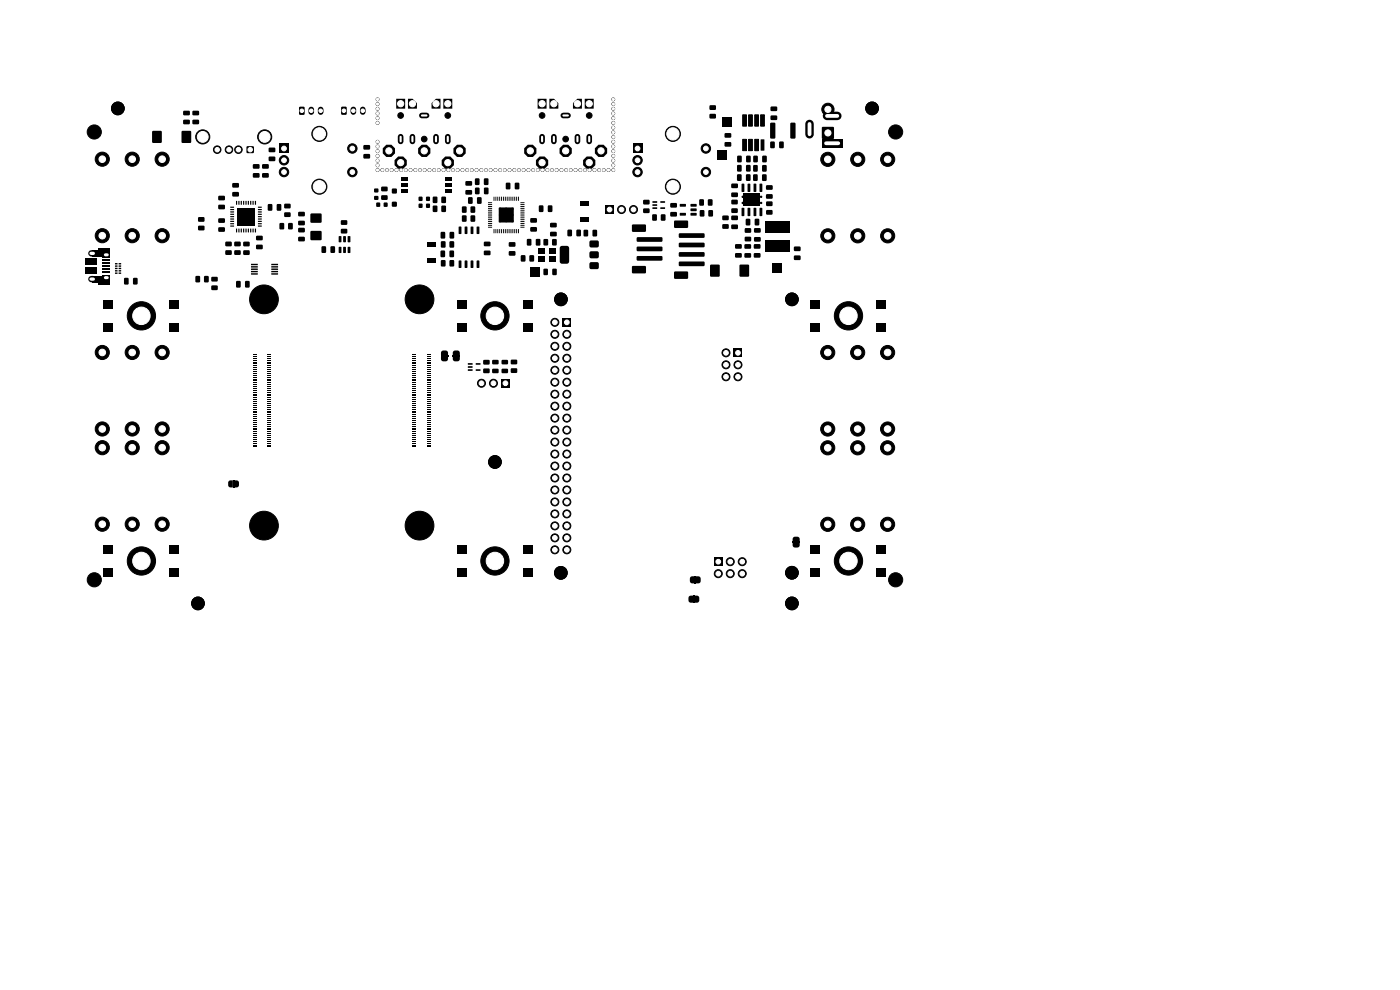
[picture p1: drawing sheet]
<svg xmlns="http://www.w3.org/2000/svg" width="297mm" height="210mm" viewBox="0 0 297 210" stroke-linecap="round" stroke-linejoin="round" font-family="sans-serif">
<g fill="#000">
<path d="M32.3 27.8h2v2.5h-2zM38.9 25.5l1.2-.1 .2 .2v.6l-.3 .2h-1l-.2-.3zM38.9 23.6l1.2-.1 .2 .2v.6l-.3 .2h-1l-.2-.3zM38.6 27.8h1.9v2.5h-1.9zM40.9 25.5l1.2-.1 .1 .2v.6l-.2 .2h-1l-.2-.3zM40.9 23.6l1.2-.1 .1 .2v.6l-.2 .2h-1l-.2-.3zM49.3 38.9l1.3-.1 .1 .3v.6l-.2 .1h-1.1l-.1-.2zM52.4 31.1h1.4v1.3h-1.4zM53.7 34.9l1.2-.1 .2 .3v.5l-.3 .2h-1l-.2-.2zM53.7 36.8l1.2-.1 .2 .3v.5l-.3 .2h-1l-.2-.2zM55.7 34.9l1.2-.1 .1 .3v.5l-.2 .2h-1.1l-.1-.2zM55.7 36.8l1.2-.1 .1 .3v.5l-.2 .2h-1.1l-.1-.2z"/>
<path d="M57 31.4l1.3-.1 .1 .3v.5l-.2 .2h-1.1l-.1-.2zM57 33.3l1.3-.1 .1 .3v.5l-.2 .2h-1.1l-.1-.2zM59.2 30.5h2.1v2h-2.1zM63.5 22.7l.9-.1 .2 .2v1.3l-.1 .3h-.8l-.3-.2zM72.4 22.7l.9-.1 .2 .2 .1 1.3-.2 .2-.8 .1-.2-.2zM77.1 30.8h1.3l.1 .2v.6l-.2 .2-1.1-.1-.1-.2zM77.1 32.7h1.3l.1 .2v.6l-.2 .2-1.1-.1-.1-.2zM79.4 40h.8v.8h-.8zM83.2 40h.9v1h-.9zM84.1 21h1.8v2h-1.8zM85.1 37.6h1.3v.8h-1.3zM85.1 38.9h1.3v.8h-1.3z"/>
<path d="M86.6 21h.9l.9 .9v1.1h-1.8zM91.6 21.9l.9-.9h.9v2h-1.8zM94.6 38.9h1.3v.8h-1.3zM94.6 37.6h1.3v.8h-1.3zM94.1 21h1.8v2h-1.8zM98.8 38.5l1.2-.1 .2 .3-.1 .5-.2 .2h-1l-.2-.2zM100.8 37.9l.7-.1 .2 .2v1l-.1 .2-.6 .1-.2-.2zM102.7 37.9l.7-.1 .2 .2v1l-.1 .2-.6 .1-.2-.2zM107.4 38.8l.6-.1 .3 .2v1l-.2 .3h-.6l-.2-.2zM109.3 38.8l.6-.1 .3 .2v1l-.2 .3h-.6l-.2-.2zM114.1 21h1.8v2h-1.8zM116.6 21h.9l.9 .9v1.1h-1.8z"/>
<path d="M121.6 21.9l.9-.9h.9v2h-1.8zM124.1 21h1.8v2h-1.8zM134.3 30.5h1.9v2h-1.9zM150.6 24.2h1.1l.2 .2v.6l-.3 .2-.9-.1-.2-.2zM150.6 22.4l1.1-.1 .2 .3v.6l-.3 .1h-.9l-.2-.2zM152.2 31.9h2v2h-2zM153.2 24.9h2v2h-2zM153.8 30.2l1.2-.1 .1 .3v.6l-.2 .1h-1.1l-.1-.2zM153.8 28.3l1.2-.1 .1 .3v.6l-.2 .1h-1.1l-.1-.2zM155.2 39l1.2-.1 .2 .3-.1 .6-.2 .1h-1l-.2-.2zM156.4 37l.7-.1 .2 .2v1l-.1 .3h-.6l-.2-.2zM156.4 35h.7l.2 .1 .1 1.1-.2 .2h-.6l-.2-.1z"/>
<path d="M156.4 33.1l.7-.1 .3 .2v1l-.2 .2-.6 .1-.2-.2zM157.4 39h.5l-.1 1.7-.5-.1zM158.6 39h.6l-.1 1.7-.5-.1zM158.3 37l.7-.1 .2 .2v1l-.1 .3h-.6l-.2-.2zM158.3 35h.7l.2 .1 .1 1.1-.2 .2h-.6l-.2-.1zM158.3 33.1l.7-.1 .3 .2v1l-.2 .2-.6 .1-.2-.2zM159.8 37h.7l.2 .1v1.1l-.1 .2h-.6l-.2-.1zM159.8 35.1l.7-.1 .2 .1 .1 1.1-.2 .2h-.6l-.2-.1zM159.9 33.1l.6-.1 .3 .2v1l-.2 .2-.6 .1-.2-.2zM159.9 39h.5v1.7l-.5-.1zM161.4 29.6h.8l-.1 2.4-.7-.1zM161.2 39h.5l-.1 1.7-.5-.1z"/>
<path d="M161.7 37h.7l.2 .1v1.1l-.1 .2h-.6l-.2-.1zM161.7 35.1l.7-.1 .2 .1 .1 1.1-.2 .2h-.6l-.2-.1zM161.8 33.1l.6-.1 .3 .2v1l-.2 .2-.6 .1-.2-.2zM163.5 24.6l1.2-.1 .2 .2v.6l-.3 .2h-1l-.2-.3zM163.5 22.7l1.2-.1 .2 .2v.6l-.3 .2h-1l-.2-.3zM163.5 30.1l.6-.1 .3 .2v1l-.2 .2-.6 .1-.2-.2zM163.4 26.1l.8-.1 .3 .2v3l-.2 .2h-.7l-.2-.1zM165.4 30.1l.6-.1 .3 .2v1l-.2 .2-.6 .1-.2-.2zM167.7 26.1l.8-.1 .3 .2v3l-.2 .2h-.7l-.2-.1zM174.4 27h2.5v2.4h-2.5zM174.3 29.5h4.4v1.8h-4.4zM18 54.8h2.5v1.4h-2.5z"/>
<path d="M18 56.7h2.5v1.5h-2.5zM19.5 53.1h2v1.3h-2zM19.5 58.6h2v1.3h-2zM20.9 52.6h.7v1.8h-.7zM20.9 58.6h.7v1.8h-.7zM21.6 55h1.7v.4h-1.7zM21.6 55.6h1.7v.4h-1.7zM21.6 56.3h1.7v.4h-1.7zM21.6 56.9h1.7v.4h-1.7zM21.6 57.6h1.7v.4h-1.7zM21.8 52.6h1.5v2h-1.5zM21.8 58.4h1.5v2h-1.5z"/>
<path d="M24.4 55.8h.5v.3h-.5zM24.4 56.3h.5v.3h-.5zM24.4 56.8h.5v.3h-.5zM24.4 57.3h.5v.3h-.5zM24.4 57.8h.5v.3h-.5zM25.2 57.8h.5v.3h-.5zM25.2 57.3h.5v.3h-.5zM25.2 56.8h.5v.3h-.5zM25.2 56.3h.5v.3h-.5zM25.2 55.8h.5v.3h-.5zM26.4 59l.6-.1 .3 .2v1l-.2 .3h-.6l-.2-.2zM28.3 59l.6-.1 .3 .2v1l-.2 .3h-.6l-.2-.2z"/>
<path d="M41.5 58.6l.7-.1 .2 .2 .1 1-.2 .2h-.6l-.2-.1zM42.1 46.1h1.1l.2 .2v.6l-.2 .2-1-.1-.2-.2zM42.1 47.9h1.1l.2 .2v.6l-.2 .2h-1l-.2-.3zM43.3 58.6l.7-.1 .3 .2v1l-.2 .2h-.6l-.2-.1zM44.9 58.8l1.2-.1 .1 .3v.6l-.2 .1h-1l-.2-.2zM46.4 43.5l1.2-.1 .1 .3v.6l-.2 .1h-1.1l-.1-.2zM46.4 41.6l1.2-.1 .1 .3v.6l-.2 .1h-1.1l-.1-.2zM46.4 46.4l1.2-.1 .1 .2v.6l-.2 .2h-1.1l-.1-.3zM46.4 48.3l1.2-.1 .1 .2v.6l-.2 .2h-1.1l-.1-.3zM47.9 51.3h1.1l.2 .2v.6l-.3 .2-1-.1-.1-.2zM47.9 53.1h1.1l.2 .2v.6l-.3 .2h-1l-.1-.3zM49.3 40.8l1.3-.1 .1 .3v.6l-.2 .1h-1.1l-.1-.2z"/>
<path d="M48.9 43.9l.7-.1 .1 .2-.8 .1zM48.9 44.4l.7-.1 .1 .2-.8 .1zM48.9 44.9l.7-.1 .1 .2-.8 .1zM48.9 45.4l.7-.1 .1 .2-.8 .1zM48.9 45.9l.7-.1 .1 .2-.8 .1zM48.9 46.4l.7-.1 .1 .2-.8 .1zM48.9 46.9l.7-.1 .1 .2-.8 .1zM48.9 47.4l.7-.1 .1 .2-.8 .1zM48.9 47.9l.7-.1 .1 .2-.8 .1zM50.1 42.6h.2v.8h-.2zM50.1 48.5h.2v.8h-.2zM50.3 44.1h3.7v3.7h-3.7z"/>
<path d="M50.6 42.6h.2v.8h-.2zM50.6 48.5h.2v.8h-.2zM49.8 51.3h1.1l.2 .2v.6l-.3 .2-1-.1-.1-.2zM49.8 53.1h1.1l.2 .2v.6l-.3 .2h-1l-.1-.3zM51.1 42.6h.2v.8h-.2zM51.1 48.5h.2v.8h-.2zM51.6 42.6h.2v.8h-.2zM51.6 48.5h.2v.8h-.2zM52.1 42.6h.2v.8h-.2zM52.1 48.5h.2v.8h-.2zM51.7 51.3h1.1l.2 .2v.6l-.3 .2h-1l-.1-.3zM51.7 53.1h1.1l.2 .2v.6l-.3 .2h-1l-.1-.3z"/>
<path d="M52.6 42.6h.2v.8h-.2zM52.6 48.5h.2v.8h-.2zM53.1 42.6h.2v.8h-.2zM53.1 48.5h.2v.8h-.2zM53.6 42.6h.2v.8h-.2zM53.6 48.5h.2v.8h-.2zM54.1 42.6h.2v.8h-.2zM54.1 48.5h.2v.8h-.2zM53.3 56h1.3l.1 .2-1.4 .1zM53.3 56.5h1.3l.1 .2-1.4 .1zM53.3 57h1.3l.1 .2-1.4 .1zM53.3 57.5h1.3l.1 .2-1.4 .1z"/>
<path d="M53.3 58h1.3l.1 .2-1.4 .1zM54.7 47.9l.8-.1v.2l-.7 .1zM54.7 47.4l.8-.1v.2l-.7 .1zM54.7 46.9l.8-.1v.2l-.7 .1zM54.7 46.4l.8-.1v.2l-.7 .1zM54.7 45.9l.8-.1v.2l-.7 .1zM54.7 45.4l.8-.1v.2l-.7 .1zM54.7 44.9l.8-.1v.2l-.7 .1zM54.7 44.4l.8-.1v.2l-.7 .1zM54.7 43.9l.8-.1v.2l-.7 .1zM54.4 50.1l1.2-.1 .2 .2-.1 .6-.2 .2h-1l-.2-.3zM54.4 52l1.2-.1 .2 .2-.1 .6-.2 .2h-1l-.2-.3z"/>
<path d="M56.9 43.3h.6l.3 .1v1.1l-.2 .2h-.6l-.2-.1zM58.8 43.3h.6l.3 .1v1.1l-.2 .2h-.6l-.2-.1zM57.6 58h1.3l.1 .2-1.4 .1zM57.6 57.5h1.3l.1 .2-1.4 .1zM57.6 57h1.3l.1 .2-1.4 .1zM57.6 56.5h1.3l.1 .2-1.4 .1zM57.6 56h1.3l.1 .2-1.4 .1zM59.3 47.4l.7-.1 .3 .1v1l-.2 .3h-.6l-.2-.2zM60.3 45.1l1.2-.1 .2 .3v.6l-.3 .1h-1l-.1-.2zM60.3 43.3l1.2-.1 .2 .2v.7l-.3 .1h-1l-.1-.2zM61.2 47.4l.7-.1 .2 .1v1l-.1 .3h-.7l-.2-.2zM63.3 46.9l1.2-.1 .2 .3v.6l-.3 .1h-1l-.2-.2z"/>
<path d="M63.3 45l1.2-.1 .2 .3v.6l-.3 .1h-1l-.2-.2zM63.3 48.4l1.2-.1 .2 .3v.6l-.3 .1h-1l-.2-.2zM63.3 50.3l1.2-.1 .2 .3v.6l-.3 .1h-1l-.2-.2zM65.9 45.3h2.3v1.9h-2.3zM65.9 49h2.3v1.9h-2.3zM68.3 52.3l.6-.1 .3 .2v1l-.2 .2-.6 .1-.2-.2zM70.2 52.3l.6-.1 .3 .2v1l-.2 .2-.6 .1-.2-.2zM71.9 52.4h.5v1.3l-.5-.1zM71.9 50.1l.5 .1v1.2l-.5-.1zM72.8 52.4h.6l-.1 1.3-.5-.1zM72.8 50.1l.6 .1-.1 1.2-.5-.1zM72.4 46.8l1.1-.1 .2 .2v.7l-.3 .1h-1l-.1-.2z"/>
<path d="M72.4 48.6l1.1-.1 .2 .3v.6l-.3 .1h-1l-.1-.2zM73.8 52.4h.5v1.3l-.5-.1zM73.8 50.1l.5 .1v1.2l-.5-.1zM79.9 43h.7v.8h-.7zM79.4 41.6h.8v.8h-.8zM80.9 41.5l1.2-.1 .1 .2v.7l-.2 .1h-1l-.2-.2zM80.9 39.6h1.2l.1 .2v.6l-.2 .2h-1l-.2-.3zM81.4 43h.8v.8h-.8zM83.2 42.8h.9v1h-.9zM85.1 40.1h1.3v.8h-1.3zM88.8 43.2h.8v.9h-.8zM88.8 41.8h.8v.8h-.8z"/>
<path d="M90.4 43.2h.8v.9h-.8zM90.4 41.8h.8v.8h-.8zM91.9 43.7l.7-.1 .2 .1v1l-.1 .3h-.7l-.2-.2zM90.7 54.9h1.7v.9h-1.7zM90.7 51.5h1.7v.9h-1.7zM91.9 41.8l.7-.1 .2 .1v1l-.1 .3h-.7l-.2-.2zM93.6 55.2h.7l.2 .1v1l-.1 .2-.6 .1-.3-.2zM93.6 51.2h.7l.2 .1v1l-.1 .2-.6 .1-.3-.2zM93.7 43.7l.7-.1 .2 .1v1l-.1 .3h-.6l-.3-.2zM93.5 53.2l.7-.1 .2 .2v1l-.1 .3h-.6l-.2-.2zM93.5 49.2h.7l.2 .1 .1 1.1-.2 .2h-.6l-.2-.1zM93.7 41.8l.7-.1 .2 .1v1l-.1 .3h-.6l-.3-.2z"/>
<path d="M95.4 55.2h.7l.2 .1 .1 1-.2 .2-.6 .1-.2-.2zM95.4 51.2h.7l.2 .1 .1 1-.2 .2-.6 .1-.2-.2zM94.6 40.1h1.3v.8h-1.3zM95.4 53.2l.7-.1 .2 .2v1l-.1 .3h-.6l-.2-.2zM95.4 49.2h.7l.2 .1 .1 1.1-.2 .2h-.6l-.2-.1zM97.3 55.3h.6l-.1 1.5h-.5zM97.3 48.1h.6l-.1 1.5h-.5zM98 43.8h.7l.3 .1v1l-.2 .2-.6 .1-.2-.2zM98 45.7h.7l.3 .1v1l-.2 .2-.6 .1-.2-.2zM98.6 55.3h.6l-.1 1.5h-.5zM98.6 48.1h.6l-.1 1.5h-.5zM98.8 40.4l1.2-.1 .2 .3-.1 .5-.2 .2h-1l-.2-.2z"/>
<path d="M99.9 43.8h.7l.2 .1v1l-.1 .2-.6 .1-.3-.2zM99.9 45.7h.7l.2 .1v1l-.1 .2-.6 .1-.3-.2zM99.9 55.3h.5l-.1 1.5h-.5zM99.9 48.1h.5l-.1 1.5h-.5zM99.4 41.9l.6-.1 .3 .2v1l-.2 .2-.6 .1-.2-.2zM101.1 55.3h.6l-.1 1.5h-.5zM101.1 48.1h.6l-.1 1.5h-.5zM100.8 39.8h.7l.2 .1v1.1l-.1 .2h-.6l-.2-.1zM101.3 41.9l.6-.1 .3 .2v1l-.2 .2-.6 .1-.2-.2zM103.5 42.9h.8l.1 .2h-.8zM103.5 43.3h.8l.1 .2h-.8zM103.5 43.7h.8l.1 .2h-.8z"/>
<path d="M103.5 44.1h.8l.1 .2h-.8zM103.5 44.5h.8l.1 .2h-.8zM103.5 44.9h.8l.1 .2h-.8zM103.5 45.3h.8l.1 .2h-.8zM103.5 45.7h.8l.1 .2h-.8zM103.5 46.1h.8l.1 .2h-.8zM103.5 46.5h.8l.1 .2h-.8zM103.5 46.9h.8l.1 .2h-.8zM103.5 47.3h.8l.1 .2h-.8zM103.5 47.7h.8l.1 .2h-.8zM103.5 48.1h.8l.1 .2h-.8zM102.7 39.8h.7l.2 .1v1.1l-.1 .2h-.6l-.2-.1z"/>
<path d="M102.7 51.3h1.2l.2 .2v.6l-.3 .2-1-.1-.2-.2zM102.7 53.2h1.2l.2 .2v.6l-.3 .2-1-.1-.2-.2zM104.7 48.6l.2 .1-.1 .8-.1-.1zM104.7 41.7l.2 .1-.1 .8h-.1zM105.1 48.6l.2 .1-.1 .8-.1-.1zM105.1 41.7l.2 .1-.1 .8h-.1zM105.5 48.6l.2 .1-.1 .8-.1-.1zM105.5 41.7l.2 .1-.1 .8h-.1zM105.8 44h3.2v3.2h-3.2zM105.9 48.6l.2 .1-.1 .8-.1-.1zM105.9 41.7l.2 .1-.1 .8h-.1zM106.3 48.6l.2 .1-.1 .8-.1-.1z"/>
<path d="M106.3 41.7l.2 .1-.1 .8h-.1zM106.7 48.6l.2 .1-.1 .8-.1-.1zM106.7 41.7l.2 .1-.1 .8h-.1zM107.1 48.6l.2 .1-.1 .8-.1-.1zM107.1 41.7l.2 .1-.1 .8h-.1zM107.5 48.6l.2 .1v.8l-.2-.1zM107.5 41.7l.2 .1v.8h-.2zM107.9 48.6l.2 .1v.8l-.2-.1zM107.9 41.7l.2 .1v.8h-.2zM108.3 48.6l.2 .1v.8l-.2-.1zM108.3 41.7l.2 .1v.8h-.2zM108.7 48.6l.2 .1v.8l-.2-.1z"/>
<path d="M108.7 41.7l.2 .1v.8h-.2zM108 51.4h1.2l.2 .2-.1 .6-.2 .2-1-.1-.2-.2zM108 53.3h1.2l.2 .2-.1 .6-.2 .2-1-.1-.2-.2zM109.1 48.6l.2 .1v.8l-.2-.1zM109.1 41.7l.2 .1v.8h-.2zM109.5 48.6l.2 .1v.8l-.2-.1zM109.5 41.7l.2 .1v.8h-.2zM109.9 48.6l.2 .1v.8l-.2-.1zM109.9 41.7l.2 .1v.8h-.2zM110.4 48.1h.8l.1 .2h-.8zM110.4 47.7h.8l.1 .2h-.8zM110.4 47.3h.8l.1 .2h-.8z"/>
<path d="M110.4 46.9h.8l.1 .2h-.8zM110.4 46.5h.8l.1 .2h-.8zM110.4 46.1h.8l.1 .2h-.8zM110.4 45.7h.8l.1 .2h-.8zM110.4 45.3h.8l.1 .2h-.8zM110.4 44.9h.8l.1 .2h-.8zM110.4 44.5h.8l.1 .2h-.8zM110.4 44.1h.8l.1 .2h-.8zM110.4 43.7h.8l.1 .2h-.8zM110.4 43.3h.8l.1 .2h-.8zM110.4 42.9h.8l.1 .2h-.8zM110.5 54.2l.7-.1 .3 .2v1l-.2 .2h-.6l-.2-.1z"/>
<path d="M112.4 54.2l.7-.1 .2 .2v1l-.1 .2h-.7l-.2-.1zM112.5 56.7h2v2h-2zM111.8 50.7h.7l.2 .1 .1 1.1-.2 .2h-.6l-.2-.1zM112.5 46.3h1.3l.1 .2v.6l-.2 .2-1.1-.1-.1-.2zM112.5 48.2h1.3l.1 .2v.6l-.2 .2-1.1-.1-.1-.2zM114.4 43.6l.7-.1 .2 .2v1l-.2 .3h-.6l-.2-.2zM113.7 50.7h.7l.2 .1 .1 1.1-.2 .2h-.6l-.2-.1zM115.3 50.8l.7-.1 .3 .1v1l-.2 .3h-.6l-.2-.2zM114.3 54.4h1.4v1.1h-1.4zM114.3 52.8h1.4v1.1h-1.4zM116.3 43.6l.7-.1 .2 .2v1l-.2 .3h-.6l-.2-.2zM115.3 57.1l.7-.1 .2 .1v1l-.1 .3h-.6l-.2-.2z"/>
<path d="M116.7 49.2h1.3l.1 .2v.6l-.2 .2-1.1-.1-.1-.2zM116.7 47.3h1.3l.1 .2v.6l-.2 .2-1.1-.1-.1-.2zM117.2 50.8l.7-.1 .2 .1v1l-.1 .3h-.6l-.3-.2zM116.5 54.4h1.4v1.1h-1.4zM116.5 52.8h1.4v1.1h-1.4zM117.2 57.1l.7-.1 .2 .1v1l-.1 .3h-.6l-.2-.2zM118.9 52.3l.2-.1h1.1l.5 .2v3.1l-.2 .4h-1.4l-.3-.2-.1-3zM120.4 48.8l.7-.1 .2 .1 .1 1.1-.2 .2h-.6l-.2-.1zM122.3 48.8l.7-.1 .2 .1 .1 1.1-.2 .2h-.6l-.2-.1zM123.9 48.8l.6-.1 .3 .2v1l-.2 .3h-.6l-.2-.2zM123.2 46.1h1.7v.9h-1.7zM123.2 42.7h1.7v.9h-1.7z"/>
<path d="M125.8 48.8l.6-.1 .3 .2v1l-.2 .3h-.6l-.2-.2zM125.1 55.8l.3-.2 1.5 .1 .1 .3v.9l-.3 .2-1.5-.1-.2-.3zM125.1 53.5l.3-.2 1.5 .1 .1 .3v.9l-.3 .2-1.5-.1-.2-.3zM125.1 51.2l.3-.2 1.5 .1 .1 .3v.9l-.3 .2-1.5-.1-.2-.3zM128.5 43.6h1.7v1.7h-1.7zM134.1 56.5l2.8-.1 .1 .3v1.1l-.2 .2h-2.6l-.2-.2zM134.1 47.7l2.8-.1 .1 .3v1.1l-.2 .2h-2.6l-.2-.2zM135.1 54.4l5.2-.1 .2 .2v.6l-.2 .2h-5l-.2-.2zM135.1 52.4l5.2-.1 .2 .2v.6l-.2 .2h-5l-.2-.2zM135.1 50.4l5.2-.1 .2 .2v.6l-.2 .2h-5l-.2-.2zM136.5 44.3l1.2-.1 .1 .2v.7l-.2 .1h-1l-.2-.2zM136.5 42.4h1.2l.1 .2v.6l-.2 .2h-1l-.2-.3z"/>
<path d="M138.4 42.7h1v.3h-.9zM138.4 43.4l1-.1v.3l-.9 .1zM138.4 44h1v.3h-.9zM138.4 45.5l.7-.1 .2 .2 .1 1-.2 .2h-.6l-.2-.1zM140.1 44h.9l.1 .3h-1zM140.1 42.7h.9l.1 .3h-1zM140.2 45.5l.7-.1 .3 .2v1l-.2 .2h-.6l-.2-.1zM143.1 57.6h2.7l.2 .2v1.2l-.3 .2h-2.6l-.1-.3zM143.1 46.8h2.7l.2 .2v1.2l-.3 .2h-2.6l-.1-.3zM142.2 43.1h1.3l.1 .2v.6l-.2 .2-1.1-.1-.1-.2zM142.2 45h1.3l.1 .2v.6l-.2 .2-1.1-.1-.1-.2zM144.1 55.5h5.1l.3 .1v.6l-.3 .3h-5l-.2-.3z"/>
<path d="M144.1 53.5h5.1l.3 .1v.6l-.3 .3h-5l-.2-.3zM144.1 51.5h5.1l.3 .1v.6l-.3 .3h-5l-.2-.3zM144.1 49.5h5.1l.3 .1v.6l-.3 .3h-5l-.2-.3zM144.2 43.3h1.2l.1 .5h-1.2zM144.2 45.2h1.2l.1 .5h-1.2zM146.5 45.2h1.2l.1 .5h-1.2zM146.5 44.2h1.2l.1 .5-1.2 .1zM146.5 43.3h1.2l.1 .5h-1.2zM148.4 42.3h.7l.2 .1v1l-.1 .2-.6 .1-.3-.2zM148.5 44.6h.7l.2 .1v1l-.1 .2-.6 .1-.3-.2zM150.2 42.3h.7l.3 .1v1l-.2 .2-.6 .1-.2-.2zM150.3 44.6h.7l.3 .1v1l-.2 .2-.6 .1-.2-.2z"/>
<path d="M150.7 56.2h1.9v2.4h-1.9zM153.3 47.6l1.2-.1 .1 .3v.6l-.2 .2-1-.1-.2-.2zM153.3 45.8l1.2-.1 .1 .3v.6l-.2 .1h-1l-.2-.2zM155.2 47.7l1.2-.1 .2 .3-.1 .6-.2 .1h-1l-.2-.2zM155.2 45.8l1.2-.1 .2 .3-.1 .6-.2 .1h-1l-.2-.2zM155.2 44.2h1.2l.1 .2v.6l-.2 .2h-1l-.2-.3zM155.2 42.4h1.2l.1 .2v.6l-.2 .2h-1l-.2-.3zM156 53.7h1.2l.2 .2v.6l-.3 .2h-1l-.2-.3zM156 51.8h1.2l.2 .2v.6l-.3 .2h-1l-.2-.3zM155.2 40.9l1.2-.1 .2 .3-.1 .6-.2 .1h-1l-.2-.2zM157.4 44.1l.5 .1-.1 1.6h-.5zM157.8 41h3.4v2.8h-3.4z"/>
<path d="M158 53.8l1.2-.1 .2 .2-.1 .6-.2 .2h-1l-.2-.3zM158 51.9l1.2-.1 .2 .2-.1 .6-.2 .2h-1l-.2-.3zM158.3 46.5l.6-.1 .3 .1v1.1l-.2 .2h-.6l-.2-.1zM156.9 56.2h2v2.4h-2zM158.6 44.1l.6 .1-.1 1.6h-.5zM158 48.4h1.2l.2 .2v.6l-.3 .2h-1l-.1-.2zM158 50.3l1.2-.1 .2 .3v.6l-.3 .1h-1l-.1-.2zM160.2 46.5l.6-.1 .3 .1v1.1l-.2 .2h-.6l-.2-.1zM160 53.7h1.2l.1 .2v.6l-.2 .2h-1.1l-.1-.3zM160 51.8h1.2l.1 .2v.6l-.2 .2h-1.1l-.1-.3zM160 50.3h1.2l.2 .2v.6l-.3 .2h-1l-.2-.3zM160 48.4h1.2l.2 .2v.6l-.3 .2h-1l-.2-.3z"/>
<path d="M159.9 44.1l.5 .1v1.6h-.5zM161.2 44.1l.5 .1-.1 1.6h-.5zM162.4 46.9h5v2.3h-5zM162.4 51h5v2.4h-5zM162.6 41.2h1.2l.1 .2v.6l-.2 .2h-1.1l-.1-.3zM162.6 39.3h1.2l.1 .2v.6l-.2 .2h-1.1l-.1-.3zM162.6 44.6l1.2-.1 .1 .3v.6l-.2 .2-1-.1-.2-.2zM162.6 42.8l1.2-.1 .1 .3v.6l-.2 .1h-1l-.2-.2zM163.8 55.9h2v2h-2zM168.5 54.3l1.2-.1 .2 .2-.1 .6-.2 .2h-1l-.2-.3zM168.5 52.4l1.2-.1 .2 .2-.1 .6-.2 .2h-1l-.2-.3zM22 63.6h2v1.8h-2z"/>
<path d="M22 68.6h2v1.8h-2zM36 63.6h2v1.8h-2zM36 68.6h2v1.8h-2zM44.9 60.6h1.2l.1 .2v.6l-.2 .2-1-.1-.2-.2zM50.1 59.6h.7l.3 .1v1.1l-.2 .2h-.6l-.2-.1zM52 59.6h.7l.3 .1v1.1l-.2 .2h-.6l-.2-.1zM53.6 79.5h.8v.2h-.8zM53.6 79.1h.8v.2h-.8zM53.6 78.7h.8v.2h-.8zM53.6 78.3h.8v.2h-.8zM53.6 77.9h.8v.2h-.8zM53.6 77.5h.8v.2h-.8z"/>
<path d="M53.6 77.1h.8v.2h-.8zM53.6 76.7h.8v.2h-.8zM53.6 76.3h.8v.2h-.8zM53.6 75.9h.8v.2h-.8zM53.6 75.5h.8v.2h-.8zM53.6 75.1h.8v.2h-.8zM56.7 79.5h.7v.2h-.7zM56.7 79.1h.7v.2h-.7zM56.7 78.7h.7v.2h-.7zM56.7 78.3h.7v.2h-.7zM56.7 77.9h.7v.2h-.7zM56.7 77.5h.7v.2h-.7z"/>
<path d="M56.7 77.1h.7v.2h-.7zM56.7 76.7h.7v.2h-.7zM56.7 76.3h.7v.2h-.7zM56.7 75.9h.7v.2h-.7zM56.7 75.5h.7v.2h-.7zM56.7 75.1h.7v.2h-.7zM87.6 79.5h.7v.2h-.7zM87.6 79.1h.7v.2h-.7zM87.6 78.7h.7v.2h-.7zM87.6 78.3h.7v.2h-.7zM87.6 77.9h.7v.2h-.7zM87.6 77.5h.7v.2h-.7z"/>
<path d="M87.6 77.1h.7v.2h-.7zM87.6 76.7h.7v.2h-.7zM87.6 76.3h.7v.2h-.7zM87.6 75.9h.7v.2h-.7zM87.6 75.5h.7v.2h-.7zM87.6 75.1h.7v.2h-.7zM90.6 79.5h.7v.2h-.7zM90.6 79.1h.7v.2h-.7zM90.6 78.7h.7v.2h-.7zM90.6 78.3h.7v.2h-.7zM90.6 77.9h.7v.2h-.7zM90.6 77.5h.7v.2h-.7z"/>
<path d="M90.6 77.1h.7v.2h-.7zM90.6 76.7h.7v.2h-.7zM90.6 76.3h.7v.2h-.7zM90.6 75.9h.7v.2h-.7zM90.6 75.5h.7v.2h-.7zM90.6 75.1h.7v.2h-.7zM93.5 75.4h1.6v.3h-1.6zM93.7 74.5l.3-.1h.7l.3 .3 .1 .7h-1.6zM93.5 75.7h1.6l-.1 .6-.4 .3h-.7l-.3-.3zM96.1 75.4h1.4v.3h-1.4zM96.2 74.5l.3-.1h.7l.3 .3v.7h-1.5zM97 63.6h2v1.8h-2z"/>
<path d="M97 68.6h2v1.8h-2zM96 75.7h1.5v.6l-.4 .3h-.7l-.3-.3zM99.3 77.1l.9-.1 .1 .3-1 .1zM99.3 77.7h.9l.1 .3h-1zM99.3 78.4l.9-.1 .1 .3-1 .1zM100.9 78.4l1-.1v.3l-.9 .1zM100.9 77.1l1-.1v.3l-.9 .1zM102.6 78.2h1.1l.2 .2v.6l-.3 .2h-1l-.1-.3zM102.6 76.4l1.1-.1 .2 .3v.6l-.3 .2-1-.1-.1-.2zM104.5 76.4l1.1-.1 .2 .3v.6l-.3 .1h-1l-.1-.2zM104.5 78.3l1.1-.1 .2 .2v.6l-.3 .2h-1l-.1-.3zM106.5 76.4l1.1-.1 .2 .3v.6l-.3 .1h-1l-.1-.2z"/>
<path d="M106.5 78.3l1.1-.1 .2 .2v.6l-.3 .2h-1l-.1-.3zM108.4 78.2l1.2-.1 .1 .3v.6l-.2 .1h-1l-.2-.2zM108.4 76.4l1.2-.1 .1 .2v.6l-.2 .2h-1l-.2-.2zM111 63.6h2v1.8h-2zM111 68.6h2v1.8h-2zM119.4 67.5h1.7v1.7h-1.7zM155.7 74h1.7v1.7h-1.7zM172 63.6h2v1.8h-2zM172 68.6h2v1.8h-2zM186 63.6h2v1.8h-2zM186 68.6h2v1.8h-2zM53.6 94.7h.8v.2h-.8z"/>
<path d="M53.6 94.3h.8v.2h-.8zM53.6 93.9h.8v.2h-.8zM53.6 93.5h.8v.2h-.8zM53.6 93.1h.8v.2h-.8zM53.6 92.7h.8v.2h-.8zM53.6 92.3h.8v.2h-.8zM53.6 91.9h.8v.2h-.8zM53.6 91.5h.8v.2h-.8zM53.6 91.1h.8v.2h-.8zM53.6 90.7h.8v.2h-.8zM53.6 90.3h.8v.2h-.8zM53.6 89.9h.8v.2h-.8z"/>
<path d="M53.6 89.5h.8v.2h-.8zM53.6 89.1h.8v.2h-.8zM53.6 88.7h.8v.2h-.8zM53.6 88.3h.8v.2h-.8zM53.6 87.9h.8v.2h-.8zM53.6 87.5h.8v.2h-.8zM53.6 87.1h.8v.2h-.8zM53.6 86.7h.8v.2h-.8zM53.6 86.3h.8v.2h-.8zM53.6 85.9h.8v.2h-.8zM53.6 85.5h.8v.2h-.8zM53.6 85.1h.8v.2h-.8z"/>
<path d="M53.6 84.7h.8v.2h-.8zM53.6 84.3h.8v.2h-.8zM53.6 83.9h.8v.2h-.8zM53.6 83.5h.8v.2h-.8zM53.6 83.1h.8v.2h-.8zM53.6 82.7h.8v.2h-.8zM53.6 82.3h.8v.2h-.8zM53.6 81.9h.8v.2h-.8zM53.6 81.5h.8v.2h-.8zM53.6 81.1h.8v.2h-.8zM53.6 80.7h.8v.2h-.8zM53.6 80.3h.8v.2h-.8z"/>
<path d="M53.6 79.9h.8v.2h-.8zM56.7 94.7h.7v.2h-.7zM56.7 94.3h.7v.2h-.7zM56.7 93.9h.7v.2h-.7zM56.7 93.5h.7v.2h-.7zM56.7 93.1h.7v.2h-.7zM56.7 92.7h.7v.2h-.7zM56.7 92.3h.7v.2h-.7zM56.7 91.9h.7v.2h-.7zM56.7 91.5h.7v.2h-.7zM56.7 91.1h.7v.2h-.7zM56.7 90.7h.7v.2h-.7z"/>
<path d="M56.7 90.3h.7v.2h-.7zM56.7 89.9h.7v.2h-.7zM56.7 89.5h.7v.2h-.7zM56.7 89.1h.7v.2h-.7zM56.7 88.7h.7v.2h-.7zM56.7 88.3h.7v.2h-.7zM56.7 87.9h.7v.2h-.7zM56.7 87.5h.7v.2h-.7zM56.7 87.1h.7v.2h-.7zM56.7 86.7h.7v.2h-.7zM56.7 86.3h.7v.2h-.7zM56.7 85.9h.7v.2h-.7z"/>
<path d="M56.7 85.5h.7v.2h-.7zM56.7 85.1h.7v.2h-.7zM56.7 84.7h.7v.2h-.7zM56.7 84.3h.7v.2h-.7zM56.7 83.9h.7v.2h-.7zM56.7 83.5h.7v.2h-.7zM56.7 83.1h.7v.2h-.7zM56.7 82.7h.7v.2h-.7zM56.7 82.3h.7v.2h-.7zM56.7 81.9h.7v.2h-.7zM56.7 81.5h.7v.2h-.7zM56.7 81.1h.7v.2h-.7z"/>
<path d="M56.7 80.7h.7v.2h-.7zM56.7 80.3h.7v.2h-.7zM56.7 79.9h.7v.2h-.7zM87.6 94.7h.7v.2h-.7zM87.6 94.3h.7v.2h-.7zM87.6 93.9h.7v.2h-.7zM87.6 93.5h.7v.2h-.7zM87.6 93.1h.7v.2h-.7zM87.6 92.7h.7v.2h-.7zM87.6 92.3h.7v.2h-.7zM87.6 91.9h.7v.2h-.7zM87.6 91.5h.7v.2h-.7z"/>
<path d="M87.6 91.1h.7v.2h-.7zM87.6 90.7h.7v.2h-.7zM87.6 90.3h.7v.2h-.7zM87.6 89.9h.7v.2h-.7zM87.6 89.5h.7v.2h-.7zM87.6 89.1h.7v.2h-.7zM87.6 88.7h.7v.2h-.7zM87.6 88.3h.7v.2h-.7zM87.6 87.9h.7v.2h-.7zM87.6 87.5h.7v.2h-.7zM87.6 87.1h.7v.2h-.7zM87.6 86.7h.7v.2h-.7z"/>
<path d="M87.6 86.3h.7v.2h-.7zM87.6 85.9h.7v.2h-.7zM87.6 85.5h.7v.2h-.7zM87.6 85.1h.7v.2h-.7zM87.6 84.7h.7v.2h-.7zM87.6 84.3h.7v.2h-.7zM87.6 83.9h.7v.2h-.7zM87.6 83.5h.7v.2h-.7zM87.6 83.1h.7v.2h-.7zM87.6 82.7h.7v.2h-.7zM87.6 82.3h.7v.2h-.7zM87.6 81.9h.7v.2h-.7z"/>
<path d="M87.6 81.5h.7v.2h-.7zM87.6 81.1h.7v.2h-.7zM87.6 80.7h.7v.2h-.7zM87.6 80.3h.7v.2h-.7zM87.6 79.9h.7v.2h-.7zM90.6 94.7h.7v.2h-.7zM90.6 94.3h.7v.2h-.7zM90.6 93.9h.7v.2h-.7zM90.6 93.5h.7v.2h-.7zM90.6 93.1h.7v.2h-.7zM90.6 92.7h.7v.2h-.7zM90.6 92.3h.7v.2h-.7z"/>
<path d="M90.6 91.9h.7v.2h-.7zM90.6 91.5h.7v.2h-.7zM90.6 91.1h.7v.2h-.7zM90.6 90.7h.7v.2h-.7zM90.6 90.3h.7v.2h-.7zM90.6 89.9h.7v.2h-.7zM90.6 89.5h.7v.2h-.7zM90.6 89.1h.7v.2h-.7zM90.6 88.7h.7v.2h-.7zM90.6 88.3h.7v.2h-.7zM90.6 87.9h.7v.2h-.7zM90.6 87.5h.7v.2h-.7z"/>
<path d="M90.6 87.1h.7v.2h-.7zM90.6 86.7h.7v.2h-.7zM90.6 86.3h.7v.2h-.7zM90.6 85.9h.7v.2h-.7zM90.6 85.5h.7v.2h-.7zM90.6 85.1h.7v.2h-.7zM90.6 84.7h.7v.2h-.7zM90.6 84.3h.7v.2h-.7zM90.6 83.9h.7v.2h-.7zM90.6 83.5h.7v.2h-.7zM90.6 83.1h.7v.2h-.7zM90.6 82.7h.7v.2h-.7z"/>
<path d="M90.6 82.3h.7v.2h-.7zM90.6 81.9h.7v.2h-.7zM90.6 81.5h.7v.2h-.7zM90.6 81.1h.7v.2h-.7zM90.6 80.7h.7v.2h-.7zM90.6 80.3h.7v.2h-.7zM90.6 79.9h.7v.2h-.7zM106.4 80.5h1.7v1.7h-1.7zM22 115.6h2v1.8h-2zM36 115.6h2v1.8h-2zM49.4 101.9h.3v1.5h-.3zM48.5 102.1l.3-.2h.6v1.5h-.6l-.3-.2z"/>
<path d="M49.7 101.9h.7l.3 .3v.8l-.3 .4h-.7zM97 115.6h2v1.8h-2zM111 115.6h2v1.8h-2zM151.5 118.3h1.7v1.7h-1.7zM168.2 114.8h1.4v.3h-1.4zM168.3 114h1.2l.1 .3v.6h-1.4v-.6zM168.2 115.2h1.4v.6l-.4 .3h-.7l-.3-.3zM172 115.6h2v1.8h-2zM186 115.6h2v1.8h-2zM22 120.6h2v1.8h-2zM36 120.6h2v1.8h-2zM97 120.6h2v1.8h-2z"/>
<path d="M111 120.6h2v1.8h-2zM146.2 126.5l.3-.1h.5v1.5l-.5-.1-.3-.1zM146.5 122.4l.9-.1v1.5l-.7-.1-.3-.3v-.7zM147 126.4h.3v1.4h-.3zM147.3 122.2h.3v1.6h-.3zM147.4 126.4h.6l.3 .3v.7l-.3 .4-.6 .1zM147.6 122.3h.7l.3 .3v.7l-.3 .4-.7 .1zM172 120.6h2v1.8h-2zM186 120.6h2v1.8h-2z"/>
<circle cx="82.5" cy="32" r="1.4"/>
<circle cx="85" cy="34.5" r="1.4"/>
<circle cx="90" cy="32" r="1.4"/>
<circle cx="95" cy="34.5" r="1.4"/>
<circle cx="97.5" cy="32" r="1.4"/>
<circle cx="112.5" cy="32" r="1.4"/>
<circle cx="115" cy="34.5" r="1.4"/>
<circle cx="120" cy="32" r="1.4"/>
<circle cx="125" cy="34.5" r="1.4"/>
<circle cx="127.5" cy="32" r="1.4"/>
</g>
<g fill="#000" stroke="#000" stroke-width=".21">
<path d="M157.6 24.4h.8v2.4h-.8zM157.6 29.6h.8v2.4h-.8zM158.8 24.4h.8v2.4h-.8zM158.8 29.6h.8v2.4h-.8zM160.1 24.4h.8v2.4h-.8zM160.1 29.6h.8v2.4h-.8zM161.4 24.4h.8v2.4h-.8z"/>
<circle cx="20" cy="28" r="1.5"/>
<circle cx="21.7" cy="33.8" r="1.5"/>
<circle cx="25" cy="23" r="1.35"/>
<circle cx="28.1" cy="33.8" r="1.5"/>
<circle cx="34.4" cy="33.8" r="1.5"/>
<circle cx="43" cy="29" r="1.5"/>
<circle cx="46.1" cy="31.7" r=".8"/>
<circle cx="48.6" cy="31.7" r=".8"/>
<circle cx="50.6" cy="31.7" r=".8"/>
<circle cx="56.1" cy="29" r="1.5"/>
<circle cx="60.2" cy="36.5" r="1"/>
<circle cx="60.3" cy="34" r="1"/>
<circle cx="67.7" cy="28.4" r="1.6"/>
<circle cx="67.7" cy="39.6" r="1.6"/>
<circle cx="74.7" cy="36.5" r="1"/>
<circle cx="74.7" cy="31.5" r="1"/>
<circle cx="80.1" cy="33.1" r=".3"/>
<circle cx="80.1" cy="24.1" r=".3"/>
<circle cx="80.1" cy="36.1" r=".3"/>
<circle cx="80.1" cy="23.1" r=".3"/>
<circle cx="80.1" cy="21.1" r=".3"/>
<circle cx="80.1" cy="26.1" r=".3"/>
<circle cx="80.1" cy="34.1" r=".3"/>
<circle cx="80.1" cy="31.1" r=".3"/>
<circle cx="80.1" cy="22.1" r=".3"/>
<circle cx="80.1" cy="30.1" r=".3"/>
<circle cx="80.1" cy="25.1" r=".3"/>
<circle cx="80.1" cy="32.1" r=".3"/>
<circle cx="80.1" cy="35.1" r=".3"/>
<circle cx="81.1" cy="36.1" r=".3"/>
<circle cx="82.1" cy="36.1" r=".3"/>
<circle cx="83.1" cy="36.1" r=".3"/>
<circle cx="84.1" cy="36.1" r=".3"/>
<circle cx="85" cy="24.5" r=".6"/>
<circle cx="85.1" cy="36.1" r=".3"/>
<circle cx="86.1" cy="36.1" r=".3"/>
<circle cx="87.1" cy="36.1" r=".3"/>
<circle cx="88.1" cy="36.1" r=".3"/>
<circle cx="89.1" cy="36.1" r=".3"/>
<circle cx="90" cy="29.5" r=".6"/>
<circle cx="90.1" cy="36.1" r=".3"/>
<circle cx="91.1" cy="36.1" r=".3"/>
<circle cx="92.1" cy="36.1" r=".3"/>
<circle cx="93.1" cy="36.1" r=".3"/>
<circle cx="94.1" cy="36.1" r=".3"/>
<circle cx="95" cy="24.5" r=".6"/>
<circle cx="95.1" cy="36.1" r=".3"/>
<circle cx="96.1" cy="36.1" r=".3"/>
<circle cx="97.1" cy="36.1" r=".3"/>
<circle cx="98.1" cy="36.1" r=".3"/>
<circle cx="99.1" cy="36.1" r=".3"/>
<circle cx="100.1" cy="36.1" r=".3"/>
<circle cx="101.1" cy="36.1" r=".3"/>
<circle cx="102.1" cy="36.1" r=".3"/>
<circle cx="103.1" cy="36.1" r=".3"/>
<circle cx="104.1" cy="36.1" r=".3"/>
<circle cx="105.1" cy="36.1" r=".3"/>
<circle cx="106.1" cy="36.1" r=".3"/>
<circle cx="107.1" cy="36.1" r=".3"/>
<circle cx="108.1" cy="36.1" r=".3"/>
<circle cx="109.1" cy="36.1" r=".3"/>
<circle cx="110.1" cy="36.1" r=".3"/>
<circle cx="111.1" cy="36.1" r=".3"/>
<circle cx="112.1" cy="36.1" r=".3"/>
<circle cx="113.1" cy="36.1" r=".3"/>
<circle cx="114.1" cy="36.1" r=".3"/>
<circle cx="115" cy="24.5" r=".6"/>
<circle cx="115.1" cy="36.1" r=".3"/>
<circle cx="116.1" cy="36.1" r=".3"/>
<circle cx="117.1" cy="36.1" r=".3"/>
<circle cx="118.1" cy="36.1" r=".3"/>
<circle cx="119.1" cy="36.1" r=".3"/>
<circle cx="120" cy="29.5" r=".6"/>
<circle cx="120.1" cy="36.1" r=".3"/>
<circle cx="121.1" cy="36.1" r=".3"/>
<circle cx="122.1" cy="36.1" r=".3"/>
<circle cx="123.1" cy="36.1" r=".3"/>
<circle cx="124.1" cy="36.1" r=".3"/>
<circle cx="125" cy="24.5" r=".6"/>
<circle cx="125.1" cy="36.1" r=".3"/>
<circle cx="126.1" cy="36.1" r=".3"/>
<circle cx="127.1" cy="36.1" r=".3"/>
<circle cx="128.1" cy="36.1" r=".3"/>
<circle cx="129.1" cy="36.1" r=".3"/>
<circle cx="130.1" cy="33.1" r=".3"/>
<circle cx="130.1" cy="24.1" r=".3"/>
<circle cx="130.1" cy="29.1" r=".3"/>
<circle cx="130.1" cy="34.1" r=".3"/>
<circle cx="130.1" cy="23.1" r=".3"/>
<circle cx="130.1" cy="36.1" r=".3"/>
<circle cx="130.1" cy="21.1" r=".3"/>
<circle cx="130.1" cy="31.1" r=".3"/>
<circle cx="130.1" cy="26.1" r=".3"/>
<circle cx="130.1" cy="28.1" r=".3"/>
<circle cx="130.1" cy="25.1" r=".3"/>
<circle cx="130.1" cy="32.1" r=".3"/>
<circle cx="130.1" cy="30.1" r=".3"/>
<circle cx="130.1" cy="27.1" r=".3"/>
<circle cx="130.1" cy="35.1" r=".3"/>
<circle cx="130.1" cy="22.1" r=".3"/>
<circle cx="135.2" cy="36.5" r="1"/>
<circle cx="135.2" cy="34" r="1"/>
<circle cx="142.7" cy="28.4" r="1.6"/>
<circle cx="142.8" cy="39.6" r="1.6"/>
<circle cx="149.7" cy="36.5" r="1"/>
<circle cx="149.7" cy="31.5" r="1"/>
<circle cx="175.6" cy="33.8" r="1.5"/>
<circle cx="175.6" cy="23.2" r="1.3"/>
<circle cx="182" cy="33.8" r="1.5"/>
<circle cx="185" cy="23" r="1.35"/>
<circle cx="188.3" cy="33.8" r="1.5"/>
<circle cx="190" cy="28" r="1.5"/>
<circle cx="21.7" cy="50" r="1.5"/>
<circle cx="28.1" cy="50" r="1.5"/>
<circle cx="34.4" cy="50" r="1.5"/>
<circle cx="106.1" cy="46.9" r=".17"/>
<circle cx="106.1" cy="44.3" r=".17"/>
<circle cx="106.1" cy="45.6" r=".17"/>
<circle cx="107.4" cy="46.9" r=".17"/>
<circle cx="107.4" cy="45.6" r=".17"/>
<circle cx="107.4" cy="44.3" r=".17"/>
<circle cx="108.7" cy="46.9" r=".17"/>
<circle cx="108.7" cy="44.3" r=".17"/>
<circle cx="108.7" cy="45.6" r=".17"/>
<circle cx="131.9" cy="44.4" r=".85"/>
<circle cx="134.4" cy="44.4" r=".85"/>
<circle cx="157.6" cy="41.8" r=".15"/>
<circle cx="157.6" cy="43.1" r=".15"/>
<circle cx="158.9" cy="43.1" r=".15"/>
<circle cx="158.9" cy="41.8" r=".15"/>
<circle cx="160.2" cy="43.1" r=".15"/>
<circle cx="160.2" cy="41.8" r=".15"/>
<circle cx="161.5" cy="43.1" r=".15"/>
<circle cx="161.5" cy="41.8" r=".15"/>
<circle cx="175.6" cy="50" r="1.5"/>
<circle cx="182" cy="50" r="1.5"/>
<circle cx="188.3" cy="50" r="1.5"/>
<circle cx="21.7" cy="74.8" r="1.5"/>
<circle cx="28.1" cy="74.8" r="1.5"/>
<circle cx="30" cy="67" r="3"/>
<circle cx="34.4" cy="74.8" r="1.5"/>
<circle cx="56" cy="63.5" r="3"/>
<circle cx="56" cy="63.5" r="1.35"/>
<circle cx="89" cy="63.5" r="3"/>
<circle cx="89" cy="63.5" r="1.35"/>
<circle cx="105" cy="67" r="3"/>
<circle cx="117.7" cy="78.5" r=".85"/>
<circle cx="117.7" cy="76" r=".85"/>
<circle cx="117.7" cy="68.4" r=".85"/>
<circle cx="117.7" cy="73.5" r=".85"/>
<circle cx="117.7" cy="70.9" r=".85"/>
<circle cx="119" cy="63.5" r="1.35"/>
<circle cx="120.3" cy="78.5" r=".85"/>
<circle cx="120.3" cy="70.9" r=".85"/>
<circle cx="120.3" cy="73.5" r=".85"/>
<circle cx="120.3" cy="76" r=".85"/>
<circle cx="154" cy="79.9" r=".85"/>
<circle cx="154" cy="74.8" r=".85"/>
<circle cx="154" cy="77.4" r=".85"/>
<circle cx="156.6" cy="79.9" r=".85"/>
<circle cx="156.6" cy="77.4" r=".85"/>
<circle cx="168" cy="63.5" r="1.35"/>
<circle cx="175.6" cy="74.8" r="1.5"/>
<circle cx="180" cy="67" r="3"/>
<circle cx="181.9" cy="74.8" r="1.5"/>
<circle cx="188.3" cy="74.8" r="1.5"/>
<circle cx="21.7" cy="95" r="1.5"/>
<circle cx="21.7" cy="91" r="1.5"/>
<circle cx="28.1" cy="95" r="1.5"/>
<circle cx="28.1" cy="91" r="1.5"/>
<circle cx="34.4" cy="95" r="1.5"/>
<circle cx="34.4" cy="91" r="1.5"/>
<circle cx="102.1" cy="81.3" r=".85"/>
<circle cx="104.7" cy="81.3" r=".85"/>
<circle cx="105" cy="98" r="1.35"/>
<circle cx="117.7" cy="93.8" r=".85"/>
<circle cx="117.7" cy="96.3" r=".85"/>
<circle cx="117.7" cy="88.7" r=".85"/>
<circle cx="117.7" cy="81.1" r=".85"/>
<circle cx="117.7" cy="83.6" r=".85"/>
<circle cx="117.7" cy="86.2" r=".85"/>
<circle cx="117.7" cy="91.2" r=".85"/>
<circle cx="117.7" cy="98.9" r=".85"/>
<circle cx="120.3" cy="86.2" r=".85"/>
<circle cx="120.3" cy="83.6" r=".85"/>
<circle cx="120.3" cy="93.8" r=".85"/>
<circle cx="120.3" cy="96.3" r=".85"/>
<circle cx="120.3" cy="88.7" r=".85"/>
<circle cx="120.3" cy="81.1" r=".85"/>
<circle cx="120.3" cy="91.2" r=".85"/>
<circle cx="120.3" cy="98.9" r=".85"/>
<circle cx="175.6" cy="91" r="1.5"/>
<circle cx="175.6" cy="95" r="1.5"/>
<circle cx="181.9" cy="91" r="1.5"/>
<circle cx="181.9" cy="95" r="1.5"/>
<circle cx="188.3" cy="91" r="1.5"/>
<circle cx="188.3" cy="95" r="1.5"/>
<circle cx="21.7" cy="111.2" r="1.5"/>
<circle cx="28.1" cy="111.2" r="1.5"/>
<circle cx="30" cy="119" r="3"/>
<circle cx="34.4" cy="111.2" r="1.5"/>
<circle cx="56" cy="111.5" r="3"/>
<circle cx="56" cy="111.5" r="1.35"/>
<circle cx="89" cy="111.5" r="3"/>
<circle cx="89" cy="111.5" r="1.35"/>
<circle cx="105" cy="119" r="3"/>
<circle cx="117.7" cy="103.9" r=".85"/>
<circle cx="117.7" cy="106.5" r=".85"/>
<circle cx="117.7" cy="116.6" r=".85"/>
<circle cx="117.7" cy="114.1" r=".85"/>
<circle cx="117.7" cy="109" r=".85"/>
<circle cx="117.7" cy="111.6" r=".85"/>
<circle cx="117.7" cy="101.4" r=".85"/>
<circle cx="120.3" cy="101.4" r=".85"/>
<circle cx="120.3" cy="103.9" r=".85"/>
<circle cx="120.3" cy="114.1" r=".85"/>
<circle cx="120.3" cy="116.6" r=".85"/>
<circle cx="120.3" cy="106.5" r=".85"/>
<circle cx="120.3" cy="109" r=".85"/>
<circle cx="120.3" cy="111.6" r=".85"/>
<circle cx="154.9" cy="119.2" r=".85"/>
<circle cx="157.5" cy="119.2" r=".85"/>
<circle cx="175.6" cy="111.2" r="1.5"/>
<circle cx="180" cy="119" r="3"/>
<circle cx="181.9" cy="111.2" r="1.5"/>
<circle cx="188.3" cy="111.2" r="1.5"/>
<circle cx="20" cy="123" r="1.5"/>
<circle cx="42" cy="128" r="1.35"/>
<circle cx="119" cy="121.5" r="1.35"/>
<circle cx="152.4" cy="121.7" r=".85"/>
<circle cx="154.9" cy="121.7" r=".85"/>
<circle cx="157.5" cy="121.7" r=".85"/>
<circle cx="168" cy="121.5" r="1.35"/>
<circle cx="168" cy="128" r="1.35"/>
<circle cx="190" cy="123" r="1.5"/>
</g>
<g fill="none" stroke="#000" stroke-width="1.2">
<path d="M66 23.2v.6M68 23.2v.6M75 23.2v.6M77 23.2v.6M85 29v1M87.5 29v1M89.5 24.5h1M92.5 29v1M95 29v1M115 29v1M117.5 29v1M119.5 24.5h1"/>
<path d="M122.5 29v1M125 29v1"/>
</g>
<path d="M171.7 26.3v2.2M175.4 24.6h2.2" fill="none" stroke="#000" stroke-width="1.8"/>
<path d="M19.4 53.7h.3M19.4 59.2h.3" fill="none" stroke="#000" stroke-width="1.3"/>
<path d="M22.4 54.1h.4M22.4 58.9h.4" fill="none" stroke="#000" stroke-width="1.1"/>
<path d="M85 29v1M87.5 29v1M89.5 24.5h1M92.5 29v1M95 29v1M115 29v1M117.5 29v1M119.5 24.5h1M122.5 29v1M125 29v1" fill="none" stroke="#fff" stroke-width=".45"/>
<g fill="#fff" stroke="#fff" stroke-width=".21">
<circle cx="28" cy="50" r=".7"/>
<circle cx="28" cy="33.8" r=".7"/>
<circle cx="21.7" cy="50" r=".7"/>
<circle cx="21.7" cy="33.8" r=".7"/>
<circle cx="34.4" cy="50" r=".7"/>
<circle cx="34.4" cy="33.8" r=".7"/>
<circle cx="28" cy="111.2" r=".7"/>
<circle cx="28" cy="95" r=".7"/>
<circle cx="21.7" cy="111.2" r=".7"/>
<circle cx="21.7" cy="95" r=".7"/>
<circle cx="34.4" cy="111.2" r=".7"/>
<circle cx="34.4" cy="95" r=".7"/>
<circle cx="175.6" cy="28.2" r=".65"/>
<circle cx="175.6" cy="23.2" r=".65"/>
<circle cx="28" cy="91" r=".7"/>
<circle cx="28" cy="74.8" r=".7"/>
<circle cx="21.7" cy="91" r=".7"/>
<circle cx="21.7" cy="74.8" r=".7"/>
<circle cx="34.4" cy="91" r=".7"/>
<circle cx="34.4" cy="74.8" r=".7"/>
<circle cx="181.9" cy="95" r=".7"/>
<circle cx="181.9" cy="111.2" r=".7"/>
<circle cx="188.3" cy="95" r=".7"/>
<circle cx="188.3" cy="111.2" r=".7"/>
<circle cx="175.6" cy="95" r=".7"/>
<circle cx="175.6" cy="111.2" r=".7"/>
<circle cx="129.3" cy="44.5" r=".5"/>
<circle cx="131.9" cy="44.5" r=".5"/>
<circle cx="134.4" cy="44.5" r=".5"/>
<circle cx="80.1" cy="21.1" r=".25"/>
<circle cx="80.1" cy="22.1" r=".25"/>
<circle cx="80.1" cy="23.1" r=".25"/>
<circle cx="80.1" cy="24.1" r=".25"/>
<circle cx="80.1" cy="25.1" r=".25"/>
<circle cx="80.1" cy="26.1" r=".25"/>
<circle cx="80.1" cy="30.1" r=".25"/>
<circle cx="80.1" cy="31.1" r=".25"/>
<circle cx="80.1" cy="32.1" r=".25"/>
<circle cx="80.1" cy="33.1" r=".25"/>
<circle cx="80.1" cy="34.1" r=".25"/>
<circle cx="80.1" cy="35.1" r=".25"/>
<circle cx="80.1" cy="36.1" r=".25"/>
<circle cx="81.1" cy="36.1" r=".25"/>
<circle cx="82.1" cy="36.1" r=".25"/>
<circle cx="83.1" cy="36.1" r=".25"/>
<circle cx="84.1" cy="36.1" r=".25"/>
<circle cx="85.1" cy="36.1" r=".25"/>
<circle cx="86.1" cy="36.1" r=".25"/>
<circle cx="87.1" cy="36.1" r=".25"/>
<circle cx="88.1" cy="36.1" r=".25"/>
<circle cx="89.1" cy="36.1" r=".25"/>
<circle cx="90.1" cy="36.1" r=".25"/>
<circle cx="91.1" cy="36.1" r=".25"/>
<circle cx="92.1" cy="36.1" r=".25"/>
<circle cx="93.1" cy="36.1" r=".25"/>
<circle cx="94.1" cy="36.1" r=".25"/>
<circle cx="95.1" cy="36.1" r=".25"/>
<circle cx="96.1" cy="36.1" r=".25"/>
<circle cx="97.1" cy="36.1" r=".25"/>
<circle cx="98.1" cy="36.1" r=".25"/>
<circle cx="99.1" cy="36.1" r=".25"/>
<circle cx="100.1" cy="36.1" r=".25"/>
<circle cx="101.1" cy="36.1" r=".25"/>
<circle cx="102.1" cy="36.1" r=".25"/>
<circle cx="103.1" cy="36.1" r=".25"/>
<circle cx="104.1" cy="36.1" r=".25"/>
<circle cx="105.1" cy="36.1" r=".25"/>
<circle cx="106.1" cy="36.1" r=".25"/>
<circle cx="107.1" cy="36.1" r=".25"/>
<circle cx="108.1" cy="36.1" r=".25"/>
<circle cx="109.1" cy="36.1" r=".25"/>
<circle cx="110.1" cy="36.1" r=".25"/>
<circle cx="111.1" cy="36.1" r=".25"/>
<circle cx="112.1" cy="36.1" r=".25"/>
<circle cx="113.1" cy="36.1" r=".25"/>
<circle cx="114.1" cy="36.1" r=".25"/>
<circle cx="115.1" cy="36.1" r=".25"/>
<circle cx="116.1" cy="36.1" r=".25"/>
<circle cx="117.1" cy="36.1" r=".25"/>
<circle cx="118.1" cy="36.1" r=".25"/>
<circle cx="119.1" cy="36.1" r=".25"/>
<circle cx="120.1" cy="36.1" r=".25"/>
<circle cx="121.1" cy="36.1" r=".25"/>
<circle cx="122.1" cy="36.1" r=".25"/>
<circle cx="123.1" cy="36.1" r=".25"/>
<circle cx="124.1" cy="36.1" r=".25"/>
<circle cx="125.1" cy="36.1" r=".25"/>
<circle cx="126.1" cy="36.1" r=".25"/>
<circle cx="127.1" cy="36.1" r=".25"/>
<circle cx="128.1" cy="36.1" r=".25"/>
<circle cx="129.1" cy="36.1" r=".25"/>
<circle cx="130.1" cy="21.1" r=".25"/>
<circle cx="130.1" cy="22.1" r=".25"/>
<circle cx="130.1" cy="23.1" r=".25"/>
<circle cx="130.1" cy="24.1" r=".25"/>
<circle cx="130.1" cy="25.1" r=".25"/>
<circle cx="130.1" cy="26.1" r=".25"/>
<circle cx="130.1" cy="27.1" r=".25"/>
<circle cx="130.1" cy="28.1" r=".25"/>
<circle cx="130.1" cy="29.1" r=".25"/>
<circle cx="130.1" cy="30.1" r=".25"/>
<circle cx="130.1" cy="31.1" r=".25"/>
<circle cx="130.1" cy="32.1" r=".25"/>
<circle cx="130.1" cy="33.1" r=".25"/>
<circle cx="130.1" cy="34.1" r=".25"/>
<circle cx="130.1" cy="35.1" r=".25"/>
<circle cx="130.1" cy="36.1" r=".25"/>
<circle cx="182" cy="33.8" r=".7"/>
<circle cx="182" cy="50" r=".7"/>
<circle cx="188.3" cy="33.8" r=".7"/>
<circle cx="188.3" cy="50" r=".7"/>
<circle cx="175.6" cy="33.8" r=".7"/>
<circle cx="175.6" cy="50" r=".7"/>
<circle cx="112.5" cy="32" r=".66"/>
<circle cx="120" cy="32" r=".66"/>
<circle cx="127.5" cy="32" r=".66"/>
<circle cx="115" cy="34.5" r=".66"/>
<circle cx="125" cy="34.5" r=".66"/>
<circle cx="122.5" cy="22" r=".66"/>
<circle cx="125" cy="22" r=".66"/>
<circle cx="115" cy="22" r=".66"/>
<circle cx="117.5" cy="22" r=".66"/>
<circle cx="60.2" cy="31.5" r=".5"/>
<circle cx="60.2" cy="36.5" r=".5"/>
<circle cx="60.2" cy="34" r=".5"/>
<circle cx="67.7" cy="28.4" r="1.3"/>
<circle cx="67.7" cy="39.6" r="1.3"/>
<circle cx="74.8" cy="36.5" r=".5"/>
<circle cx="74.8" cy="31.5" r=".5"/>
<circle cx="107.2" cy="81.3" r=".5"/>
<circle cx="104.7" cy="81.3" r=".5"/>
<circle cx="102.1" cy="81.3" r=".5"/>
<circle cx="181.9" cy="74.8" r=".7"/>
<circle cx="181.9" cy="91" r=".7"/>
<circle cx="188.3" cy="74.8" r=".7"/>
<circle cx="188.3" cy="91" r=".7"/>
<circle cx="175.6" cy="74.8" r=".7"/>
<circle cx="175.6" cy="91" r=".7"/>
<circle cx="53.1" cy="31.8" r=".47"/>
<circle cx="50.6" cy="31.8" r=".47"/>
<circle cx="48.6" cy="31.8" r=".47"/>
<circle cx="46.1" cy="31.8" r=".47"/>
<circle cx="56.1" cy="29" r="1.15"/>
<circle cx="43" cy="29" r="1.15"/>
<circle cx="135.3" cy="31.5" r=".5"/>
<circle cx="135.3" cy="36.5" r=".5"/>
<circle cx="135.3" cy="34" r=".5"/>
<circle cx="142.8" cy="28.4" r="1.3"/>
<circle cx="142.8" cy="39.6" r="1.3"/>
<circle cx="149.7" cy="36.5" r=".5"/>
<circle cx="149.7" cy="31.5" r=".5"/>
<circle cx="82.5" cy="32" r=".66"/>
<circle cx="90" cy="32" r=".66"/>
<circle cx="97.5" cy="32" r=".66"/>
<circle cx="85" cy="34.5" r=".66"/>
<circle cx="95" cy="34.5" r=".66"/>
<circle cx="92.5" cy="22" r=".66"/>
<circle cx="95" cy="22" r=".66"/>
<circle cx="85" cy="22" r=".66"/>
<circle cx="87.5" cy="22" r=".66"/>
<circle cx="30" cy="119" r="1.85"/>
<circle cx="105" cy="67" r="1.85"/>
<circle cx="30" cy="67" r="1.85"/>
<circle cx="180" cy="67" r="1.85"/>
<circle cx="105" cy="119" r="1.85"/>
<circle cx="73" cy="23.5" r=".37"/>
<circle cx="75" cy="23.5" r=".37"/>
<circle cx="77" cy="23.5" r=".37"/>
<circle cx="180" cy="119" r="1.85"/>
<circle cx="120.3" cy="68.4" r=".5"/>
<circle cx="117.7" cy="68.4" r=".5"/>
<circle cx="120.3" cy="70.9" r=".5"/>
<circle cx="117.7" cy="70.9" r=".5"/>
<circle cx="120.3" cy="73.5" r=".5"/>
<circle cx="117.7" cy="73.5" r=".5"/>
<circle cx="120.3" cy="76" r=".5"/>
<circle cx="117.7" cy="76" r=".5"/>
<circle cx="120.3" cy="78.5" r=".5"/>
<circle cx="117.7" cy="78.5" r=".5"/>
<circle cx="120.3" cy="81.1" r=".5"/>
<circle cx="117.7" cy="81.1" r=".5"/>
<circle cx="120.3" cy="83.6" r=".5"/>
<circle cx="117.7" cy="83.6" r=".5"/>
<circle cx="120.3" cy="86.2" r=".5"/>
<circle cx="117.7" cy="86.2" r=".5"/>
<circle cx="120.3" cy="88.7" r=".5"/>
<circle cx="117.7" cy="88.7" r=".5"/>
<circle cx="120.3" cy="91.2" r=".5"/>
<circle cx="117.7" cy="91.2" r=".5"/>
<circle cx="120.3" cy="93.8" r=".5"/>
<circle cx="117.7" cy="93.8" r=".5"/>
<circle cx="120.3" cy="96.3" r=".5"/>
<circle cx="117.7" cy="96.3" r=".5"/>
<circle cx="120.3" cy="98.9" r=".5"/>
<circle cx="117.7" cy="98.9" r=".5"/>
<circle cx="120.3" cy="101.4" r=".5"/>
<circle cx="117.7" cy="101.4" r=".5"/>
<circle cx="120.3" cy="103.9" r=".5"/>
<circle cx="117.7" cy="103.9" r=".5"/>
<circle cx="120.3" cy="106.5" r=".5"/>
<circle cx="117.7" cy="106.5" r=".5"/>
<circle cx="120.3" cy="109" r=".5"/>
<circle cx="117.7" cy="109" r=".5"/>
<circle cx="120.3" cy="111.6" r=".5"/>
<circle cx="117.7" cy="111.6" r=".5"/>
<circle cx="120.3" cy="114.1" r=".5"/>
<circle cx="117.7" cy="114.1" r=".5"/>
<circle cx="120.3" cy="116.6" r=".5"/>
<circle cx="117.7" cy="116.6" r=".5"/>
<circle cx="156.6" cy="74.8" r=".5"/>
<circle cx="154" cy="74.8" r=".5"/>
<circle cx="156.6" cy="77.4" r=".5"/>
<circle cx="154" cy="77.4" r=".5"/>
<circle cx="156.6" cy="79.9" r=".5"/>
<circle cx="154" cy="79.9" r=".5"/>
<circle cx="152.4" cy="119.2" r=".5"/>
<circle cx="152.4" cy="121.7" r=".5"/>
<circle cx="154.9" cy="119.2" r=".5"/>
<circle cx="154.9" cy="121.7" r=".5"/>
<circle cx="157.5" cy="119.2" r=".5"/>
<circle cx="157.5" cy="121.7" r=".5"/>
<circle cx="64" cy="23.5" r=".38"/>
<circle cx="66" cy="23.5" r=".38"/>
<circle cx="68" cy="23.5" r=".38"/>
</g>
<path d="M171.7 26.3v2.2M175.2 30.4h2.6M175.4 24.6h2.2" fill="none" stroke="#fff" stroke-width=".8"/>
<path d="M19.3 53.7h.5M19.3 59.2h.5" fill="none" stroke="#fff" stroke-width=".7"/>
<path d="M22.4 54.1h.4M22.4 58.9h.4" fill="none" stroke="#fff" stroke-width=".65"/>
</svg>
